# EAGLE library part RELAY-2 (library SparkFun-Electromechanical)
SPDT relay (COM-00100)

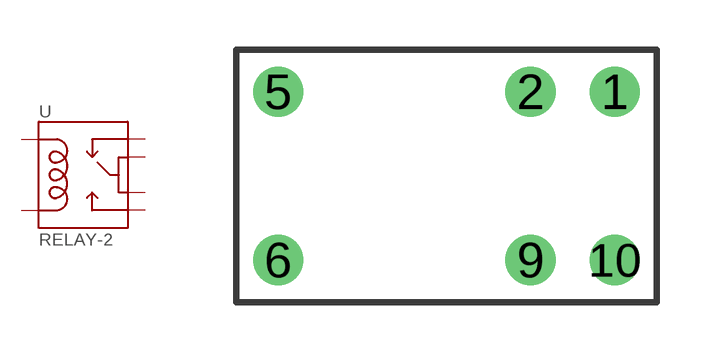
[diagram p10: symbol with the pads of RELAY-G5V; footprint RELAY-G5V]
Designator prefix -

## RELAY-2G5Q  [RELAY-G5V]
1  1
2  2
5  5
6  6
9  9
10  10

## Footprint RELAY-G5V (pad centres in mm)
G5Q SPDT Relay (SparkFun SKU: COM-00100). Footprint should also work with SPST-NO relay.
drill 1.016: 1 5.08,2.54; 2 2.54,2.54; 5 -5.08,2.54; 6 -5.08,-2.54; 9 2.54,-2.54; 10 5.08,-2.54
